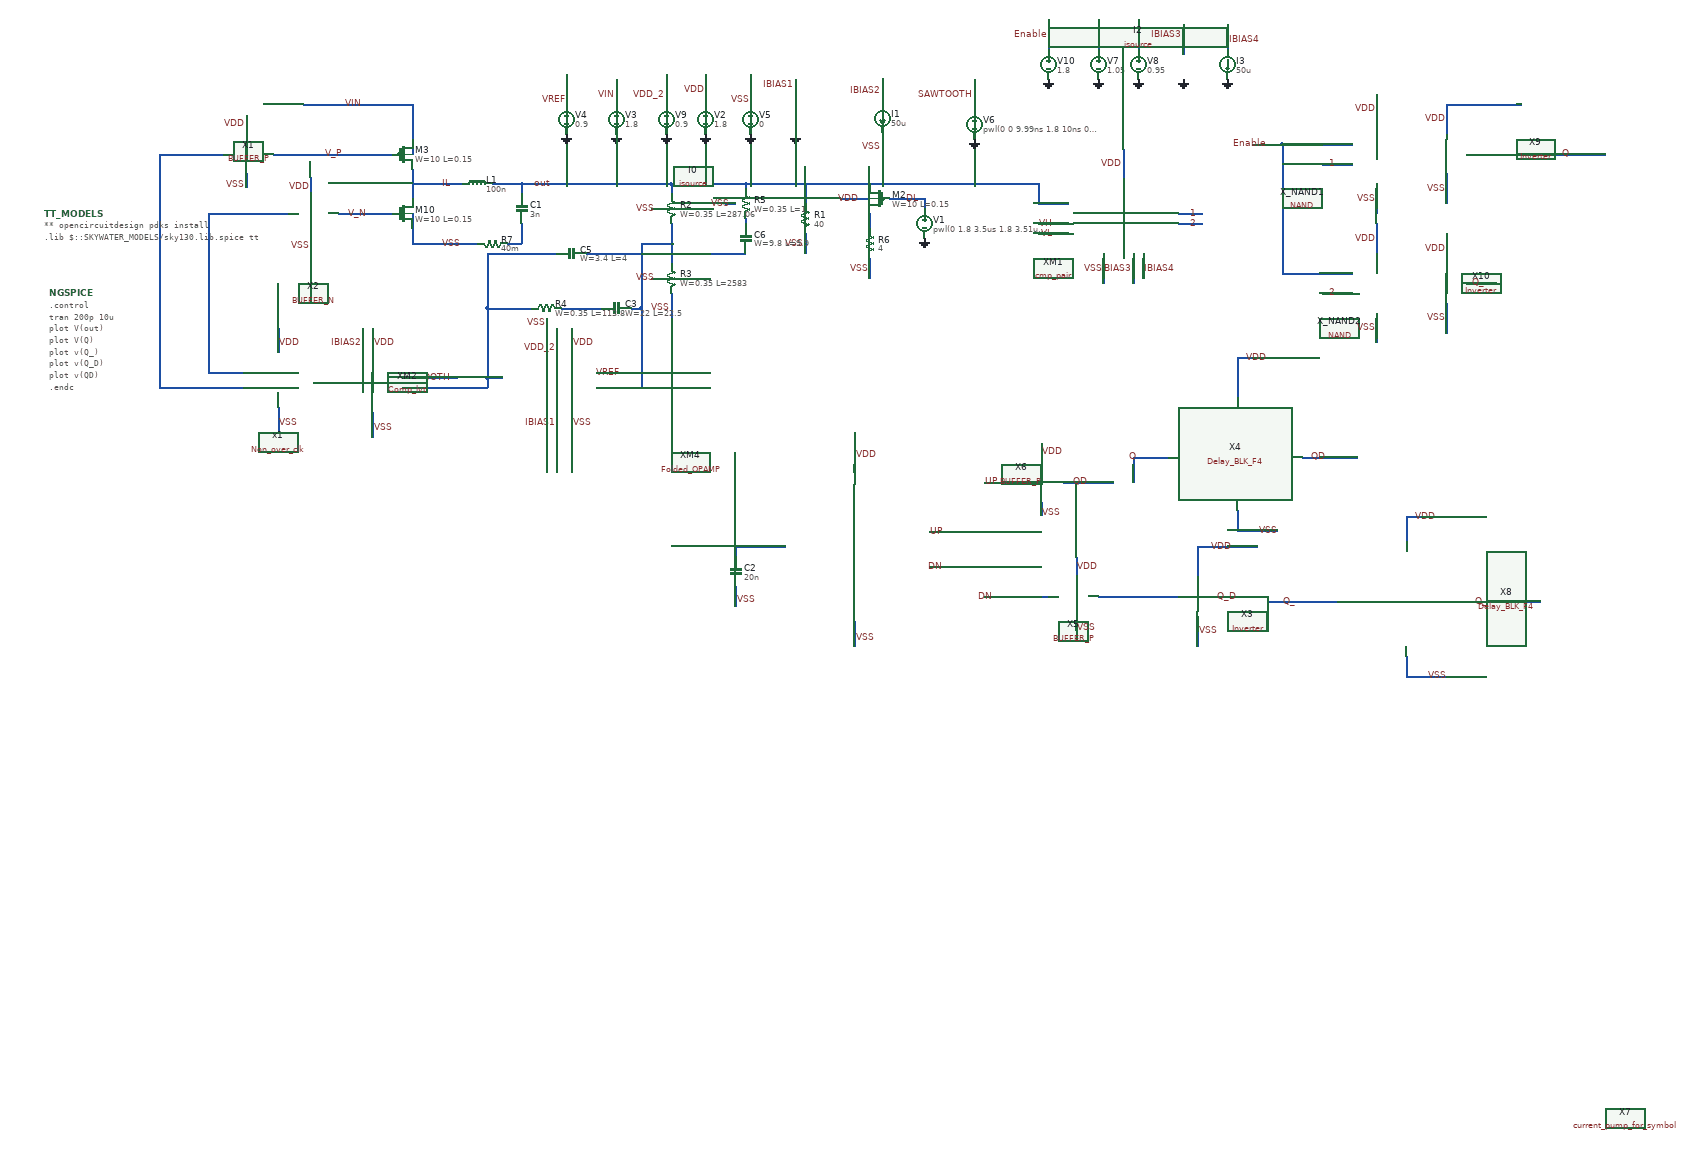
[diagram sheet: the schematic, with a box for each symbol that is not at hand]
v {xschem version=3.0.0 file_version=1.2 }
G {}
K {}
V {}
S {}
E {}
N 2100 -2270 2100 -2210 {
lab=IL}
N 2100 -2330 2100 -2300 {
lab=VIN}
N 2010 -2300 2060 -2300 {
lab=V_P}
N 2100 -2400 2100 -2330 {
lab=VIN}
N 1880 -2400 2100 -2400 {
lab=VIN}
N 2100 -2150 2100 -2120 {
lab=VSS}
N 2100 -2240 2160 -2240 {
lab=IL}
N 2160 -2240 2200 -2240 {
lab=IL}
N 2320 -2240 2320 -2220 {
lab=out}
N 2260 -2240 2320 -2240 {
lab=out}
N 2320 -2160 2320 -2120 {
lab=#net1}
N 2320 -2240 2430 -2240 {
lab=out}
N 2420 -1950 2420 -1900 {
lab=VDD}
N 2390 -1950 2390 -1900 {
lab=VDD_2}
N 2420 -1790 2420 -1740 {
lab=VSS}
N 2390 -1790 2390 -1740 {
lab=IBIAS1}
N 2470 -1830 2520 -1830 {
lab=#net2}
N 2470 -1860 2520 -1860 {
lab=VREF}
N 2510 -2450 2510 -2400 {
lab=VIN}
N 2610 -2460 2610 -2400 {
lab=VDD_2}
N 2690 -2410 2690 -2400 {
lab=VDD}
N 2690 -2460 2690 -2410 {
lab=VDD}
N 2780 -2430 2780 -2410 {
lab=VSS}
N 2780 -2410 2780 -2400 {
lab=VSS}
N 2780 -2460 2780 -2430 {
lab=VSS}
N 2870 -2450 2870 -2390 {
lab=IBIAS1}
N 2020 -1950 2020 -1900 {
lab=VDD}
N 2020 -1780 2020 -1730 {
lab=VSS}
N 2410 -2430 2410 -2410 {
lab=VREF}
N 2410 -2410 2410 -2400 {
lab=VREF}
N 2410 -2460 2410 -2430 {
lab=VREF}
N 2520 -1830 2550 -1830 {
lab=#net2}
N 3045 -2342.5 3045 -2292.5 {
lab=VSS}
N 2000 -1950 2000 -1900 {
lab=IBIAS2}
N 3230 -2450 3230 -2390 {
lab=SAWTOOTH}
N 1820 -2300 2010 -2300 {
lab=V_P}
N 2430 -2240 2610 -2240 {
lab=out}
N 2620 -2240 2620 -2220 {
lab=out}
N 2620 -2160 2620 -2110 {
lab=#net2}
N 2620 -2020 2620 -1970 {
lab=VSS}
N 2400 -1990 2480 -1990 {
lab=#net3}
N 2250 -1990 2340 -1990 {
lab=#net4}
N 2250 -1990 2250 -1850 {
lab=#net4}
N 2560 -1990 2560 -1860 {
lab=#net2}
N 2540 -1990 2560 -1990 {
lab=#net2}
N 2250 -2100 2390 -2100 {
lab=#net4}
N 2450 -2100 2560 -2100 {
lab=#net2}
N 2560 -2060 2560 -1990 {
lab=#net2}
N 2250 -1850 2280 -1850 {
lab=#net4}
N 2560 -1860 2560 -1830 {
lab=#net2}
N 2550 -1830 2560 -1830 {
lab=#net2}
N 2620 -2240 2770 -2240 {
lab=out}
N 2770 -2240 2770 -2230 {
lab=out}
N 2770 -2170 2770 -2160 {
lab=#net5}
N 2610 -2240 2620 -2240 {
lab=out}
N 2560 -2120 2560 -2060 {
lab=#net2}
N 2560 -2120 2620 -2120 {
lab=#net2}
N 2620 -2110 2620 -2080 {
lab=#net2}
N 2890 -2240 2890 -2200 {
lab=out}
N 2770 -2240 2890 -2240 {
lab=out}
N 2890 -2140 2890 -2100 {
lab=VSS}
N 2080 -1830 2250 -1830 {
lab=#net4}
N 2250 -1850 2250 -1830 {
lab=#net4}
N 2010 -2180 2060 -2180 {
lab=V_N}
N 2100 -2180 2100 -2150 {
lab=VSS}
N 2890 -2240 3020 -2240 {
lab=out}
N 3020 -2090 3020 -2050 {
lab=VSS}
N 3020 -2180 3020 -2150 {
lab=#net6}
N 3060 -2210 3130 -2210 {
lab=DL}
N 3130 -2210 3130 -2190 {
lab=DL}
N 1830 -1950 1830 -1900 {
lab=VDD}
N 1830 -1790 1830 -1740 {
lab=VSS}
N 1590 -2300 1720 -2300 {
lab=#net7}
N 1590 -2300 1590 -1860 {
lab=#net7}
N 1765 -2260 1765 -2232.5 {
lab=VSS}
N 1765 -2377.5 1765 -2342.5 {
lab=VDD}
N 1950 -2180 2010 -2180 {
lab=V_N}
N 1690 -2180 1850 -2180 {
lab=#net8}
N 1690 -2180 1690 -2090 {
lab=#net8}
N 1895 -2140 1895 -2102.5 {
lab=VSS}
N 1895 -2252.5 1895 -2222.5 {
lab=VDD}
N 1690 -1860 1750 -1860 {
lab=#net8}
N 1690 -2090 1690 -1860 {
lab=#net8}
N 1590 -1830 1750 -1830 {
lab=#net7}
N 1590 -1860 1590 -1830 {
lab=#net7}
N 2250 -2100 2250 -1990 {
lab=#net4}
N 2620 -2100 2670 -2100 {
lab=#net2}
N 2670 -2100 2770 -2100 {
lab=#net2}
N 2420 -1790 2420 -1740 {
lab=VSS}
N 2960 -2210 3020 -2210 {
lab=VDD}
N 3045 -2452.5 3045 -2402.5 {
lab=IBIAS2}
N 1900 -1840 1950 -1840 {
lab=#net9}
N 2080 -1850 2190 -1850 {
lab=SAWTOOTH}
N 2370 -1970 2370 -1950 {
lab=VSS}
N 2730 -2200 2750 -2200 {
lab=VSS}
N 2580 -2190 2600 -2190 {
lab=VSS}
N 2580 -2050 2600 -2050 {
lab=VSS}
N 2100 -2120 2230 -2120 {
lab=VSS}
N 2290 -2120 2320 -2120 {
lab=#net1}
N 3640 -2180 3690 -2180 {
lab=1}
N 3640 -2160 3690 -2160 {
lab=2}
N 3570 -2100 3570 -2050 {
lab=IBIAS4}
N 3550 -2100 3550 -2040 {
lab=IBIAS3}
N 3490 -2100 3490 -2040 {
lab=VSS}
N 3530 -2310 3530 -2250 {
lab=VDD}
N 3360 -2200 3420 -2200 {
lab=out}
N 3360 -2160 3420 -2160 {
lab=VH}
N 3360 -2140 3420 -2140 {
lab=VL}
N 3020 -2240 3360 -2240 {
lab=out}
N 3360 -2240 3360 -2200 {
lab=out}
N 3480 -2570 3480 -2510 {
lab=VH}
N 3560 -2570 3560 -2510 {
lab=VL}
N 3650 -2560 3650 -2500 {
lab=IBIAS3}
N 3740 -2560 3740 -2510 {
lab=IBIAS4}
N 4040 -2420 4040 -2360 {
lab=VDD}
N 4040 -2240 4040 -2180 {
lab=VSS}
N 4040 -2160 4040 -2100 {
lab=VDD}
N 4040 -1980 4040 -1920 {
lab=VSS}
N 3850 -2060 3990 -2060 {
lab=Enable}
N 3850 -2320 3850 -2060 {
lab=Enable}
N 3850 -2320 3990 -2320 {
lab=Enable}
N 3790 -2320 3850 -2320 {
lab=Enable}
N 3930 -2280 3990 -2280 {
lab=1}
N 3930 -2020 3990 -2020 {
lab=2}
N 4220 -2300 4280 -2300 {
lab=Q}
N 4220 -2040 4280 -2040 {
lab=Q_}
N 4180 -2400 4180 -2340 {
lab=VDD}
N 4180 -2260 4180 -2200 {
lab=VSS}
N 4180 -2140 4180 -2080 {
lab=VDD}
N 4180 -2000 4180 -1940 {
lab=VSS}
N 4280 -2300 4290 -2300 {
lab=Q}
N 4180 -2400 4330 -2400 {
lab=VDD}
N 4290 -2300 4500 -2300 {
lab=Q}
N 3380 -2570 3380 -2510 {
lab=Enable}
N 3480 -1410 3580 -1410 {
lab=#net10}
N 3410 -1640 3510 -1640 {
lab=QD}
N 3435 -1370 3435 -1342.5 {
lab=VSS}
N 3435 -1487.5 3435 -1452.5 {
lab=VDD}
N 3365 -1600 3365 -1572.5 {
lab=VSS}
N 3365 -1717.5 3365 -1682.5 {
lab=VDD}
N 3250 -1410 3310 -1410 {
lab=DN}
N 3140 -1540 3180 -1540 {
lab=UP}
N 3250 -1640 3310 -1640 {
lab=UP}
N 3140 -1470 3180 -1470 {
lab=DN}
N 2990 -1720 2990 -1660 {
lab=VDD}
N 2990 -1360 2990 -1310 {
lab=VSS}
N 2990 -1740 2990 -1720 {
lab=VDD}
N 3310 -1410 3380 -1410 {
lab=DN}
N 3580 -1410 3640 -1410 {
lab=#net10}
N 3680 -1510 3680 -1450 {
lab=VDD}
N 3680 -1370 3680 -1310 {
lab=VSS}
N 3680 -1510 3800 -1510 {
lab=VDD}
N 3550 -1690 3620 -1690 {
lab=Q}
N 3550 -1690 3550 -1640 {
lab=Q}
N 3820 -1400 3960 -1400 {
lab=Q_}
N 3820 -1410 3820 -1400 {
lab=Q_}
N 3890 -1690 4000 -1690 {
lab=QD}
N 4230 -1400 4370 -1400 {
lab=Q_D}
N 3720 -1410 3760 -1410 {
lab=Q_D}
N 3760 -1890 3760 -1810 {
lab=VDD}
N 3760 -1582.5 3760 -1542.5 {
lab=VSS}
N 3760 -1542.5 3840 -1542.5 {
lab=VSS}
N 4100 -1570 4100 -1520 {
lab=VDD}
N 4100 -1570 4130 -1570 {
lab=VDD}
N 3760 -1890 3790 -1890 {
lab=VDD}
N 4100 -1290 4100 -1250 {
lab=VSS}
N 4100 -1250 4180 -1250 {
lab=VSS}
N 2750 -1510 2750 -1490 {
lab=#net9}
N 2750 -1430 2750 -1390 {
lab=VSS}
N 2750 -1510 2850 -1510 {}
N 1750 -1860 1760 -1860 {}
N 1750 -1830 1760 -1830 {}
C {sky130_fd_pr/pfet_01v8.sym} 2080 -2300 0 0 {name=M3
L=0.15
W=10
nf=1
mult=450
ad="'int((nf+1)/2) * W/nf * 0.29'" 
pd="'2*int((nf+1)/2) * (W/nf + 0.29)'"
as="'int((nf+2)/2) * W/nf * 0.29'" 
ps="'2*int((nf+2)/2) * (W/nf + 0.29)'"
nrd="'0.29 / W'" nrs="'0.29 / W'"
sa=0 sb=0 sd=0
model=pfet_01v8
spiceprefix=X
}
C {devices/ind.sym} 2230 -2240 3 0 {name=L1
m=1
value=100n
footprint=1206
device=inductor}
C {devices/capa.sym} 2320 -2190 0 0 {name=C1
m=1
value=3n
footprint=1206
device="ceramic capacitor"}
C {devices/code.sym} 1360 -2180 0 0 {name=TT_MODELS
only_toplevel=true
format="tcleval( @value )"
value="
** opencircuitdesign pdks install
.lib $::SKYWATER_MODELS/sky130.lib.spice tt

"
spice_ignore=false}
C {devices/code_shown.sym} 1370 -2020 0 0 {name=NGSPICE
only_toplevel=true
value="

.control

tran 200p 10u
plot  V(out)
plot V(Q)
plot v(Q_) 
plot v(Q_D)
plot v(QD)
.endc
" }
C {devices/lab_wire.sym} 2380 -2240 0 0 {name=l4 sig_type=std_logic lab=out}
C {devices/lab_wire.sym} 2180 -2240 0 0 {name=l6 sig_type=std_logic lab=IL}
C {devices/lab_wire.sym} 2000 -2400 0 0 {name=l5 sig_type=std_logic lab=VIN}
C {devices/vsource.sym} 2510 -2370 0 0 {name=V3 value=1.8}
C {devices/gnd.sym} 2510 -2340 0 0 {name=l7 lab=GND}
C {devices/lab_wire.sym} 2510 -2420 0 0 {name=l2 sig_type=std_logic lab=VIN}
C {devices/gnd.sym} 2870 -2340 0 0 {name=l19 lab=GND}
C {devices/lab_wire.sym} 2870 -2440 0 0 {name=l22 sig_type=std_logic lab=IBIAS1}
C {devices/isource.sym} 2870 -2370 0 0 {name=I0 value=50u}
C {devices/vsource.sym} 2610 -2370 0 0 {name=V9 value=0.9}
C {devices/gnd.sym} 2610 -2340 0 0 {name=l42 lab=GND}
C {devices/lab_wire.sym} 2610 -2420 0 0 {name=l8 sig_type=std_logic lab=VDD_2}
C {devices/vsource.sym} 2690 -2370 0 0 {name=V2 value=1.8}
C {devices/gnd.sym} 2690 -2340 0 0 {name=l18 lab=GND}
C {devices/vsource.sym} 2780 -2370 0 0 {name=V5 value=0}
C {devices/gnd.sym} 2780 -2340 0 0 {name=l26 lab=GND}
C {devices/lab_wire.sym} 2780 -2410 0 0 {name=l10 sig_type=std_logic lab=VSS}
C {devices/lab_wire.sym} 2420 -1920 0 1 {name=l13 sig_type=std_logic lab=VDD}
C {devices/lab_wire.sym} 2390 -1910 0 0 {name=l14 sig_type=std_logic lab=VDD_2}
C {devices/lab_wire.sym} 2200 -2120 0 0 {name=l1 sig_type=std_logic lab=VSS}
C {devices/lab_wire.sym} 2420 -1760 0 1 {name=l15 sig_type=std_logic lab=VSS}
C {devices/lab_wire.sym} 2390 -1760 0 0 {name=l16 sig_type=std_logic lab=IBIAS1}
C {devices/lab_wire.sym} 2020 -1920 0 1 {name=l11 sig_type=std_logic lab=VDD}
C {devices/lab_wire.sym} 2020 -1750 0 1 {name=l12 sig_type=std_logic lab=VSS}
C {devices/vsource.sym} 2410 -2370 0 0 {name=V4 value=0.9}
C {devices/gnd.sym} 2410 -2340 0 0 {name=l17 lab=GND}
C {devices/lab_wire.sym} 2410 -2410 0 0 {name=l20 sig_type=std_logic lab=VREF}
C {devices/isource.sym} 3045 -2372.5 0 1 {name=I1 value=50u}
C {devices/lab_wire.sym} 2000 -1920 0 0 {name=l27 sig_type=std_logic lab=IBIAS2}
C {devices/vsource.sym} 3230 -2360 0 0 {name=V6 value="pwl(0 0 9.99ns 1.8 10ns 0) r=0"}
C {devices/gnd.sym} 3230 -2330 0 0 {name=l28 lab=GND}
C {devices/gnd.sym} 3230 -2330 0 0 {name=l29 lab=GND}
C {devices/lab_wire.sym} 3230 -2420 0 0 {name=l30 sig_type=std_logic lab=SAWTOOTH}
C {devices/lab_wire.sym} 2620 -1990 0 0 {name=l31 sig_type=std_logic lab=VSS}
C {devices/lab_wire.sym} 2520 -1860 0 0 {name=l33 sig_type=std_logic lab=VREF}
C {devices/lab_wire.sym} 2180 -1850 0 0 {name=l32 sig_type=std_logic lab=SAWTOOTH}
C {devices/lab_wire.sym} 2890 -2120 0 0 {name=l21 sig_type=std_logic lab=VSS}
C {sky130_fd_pr/pfet_01v8.sym} 3040 -2210 0 1 {name=M2
L=0.15
W=10
nf=1
mult=450
ad="'int((nf+1)/2) * W/nf * 0.29'" 
pd="'2*int((nf+1)/2) * (W/nf + 0.29)'"
as="'int((nf+2)/2) * W/nf * 0.29'" 
ps="'2*int((nf+2)/2) * (W/nf + 0.29)'"
nrd="'0.29 / W'" nrs="'0.29 / W'"
sa=0 sb=0 sd=0
model=pfet_01v8
spiceprefix=X
}
C {devices/lab_wire.sym} 3020 -2070 0 0 {name=l23 sig_type=std_logic lab=VSS}
C {devices/vsource.sym} 3130 -2160 0 0 {name=V1 value="pwl(0 1.8 3.5us 1.8 3.51us 0 7us 0) r=0"}
C {devices/gnd.sym} 3130 -2130 0 0 {name=l34 lab=GND}
C {devices/gnd.sym} 3130 -2130 0 0 {name=l36 lab=GND}
C {devices/lab_wire.sym} 1830 -1920 0 1 {name=l35 sig_type=std_logic lab=VDD}
C {devices/lab_wire.sym} 1830 -1760 0 1 {name=l37 sig_type=std_logic lab=VSS}
C {DC_DC_Converter/BUFFER/BUFFER_PMOS/BUFFER_P.sym} 1700 -2250 0 0 {name=X1}
C {devices/lab_wire.sym} 1765 -2360 0 0 {name=l38 sig_type=std_logic lab=VDD}
C {devices/lab_wire.sym} 1765 -2237.5 0 0 {name=l40 sig_type=std_logic lab=VSS}
C {devices/lab_wire.sym} 1895 -2115 0 0 {name=l39 sig_type=std_logic lab=VSS}
C {devices/lab_wire.sym} 1895 -2235 0 0 {name=l41 sig_type=std_logic lab=VDD}
C {devices/lab_wire.sym} 1960 -2300 0 0 {name=l3 sig_type=std_logic lab=V_P}
C {devices/lab_wire.sym} 2010 -2180 0 0 {name=l43 sig_type=std_logic lab=V_N}
C {DC_DC_Converter/Folded_OPAMP/Folded_OPAMP.sym} 2480 -1790 0 1 {name=XM4}
C {devices/lab_wire.sym} 3120 -2210 0 0 {name=l96 sig_type=std_logic lab=DL}
C {sky130_fd_pr/cap_mim_m3_1.sym} 2420 -2100 3 0 {name=C5 model=cap_mim_m3_1 W=3.4 L=4 MF=1 spiceprefix=X}
C {sky130_fd_pr/cap_mim_m3_1.sym} 2510 -1990 3 0 {name=C3 model=cap_mim_m3_1 W=22 L=22.5 MF=1 spiceprefix=X}
C {sky130_fd_pr/cap_mim_m3_1.sym} 2770 -2130 0 0 {name=C6 model=cap_mim_m3_1 W=9.8 L=9.9 MF=1 spiceprefix=X}
C {devices/lab_wire.sym} 2690 -2430 0 0 {name=l97 sig_type=std_logic lab=VDD}
C {devices/lab_wire.sym} 3000 -2210 0 0 {name=l98 sig_type=std_logic lab=VDD}
C {sky130_fd_pr/nfet_01v8.sym} 2080 -2180 0 0 {name=M10
L=0.15
W=10
nf=1 
mult=150
ad="'int((nf+1)/2) * W/nf * 0.29'" 
pd="'2*int((nf+1)/2) * (W/nf + 0.29)'"
as="'int((nf+2)/2) * W/nf * 0.29'" 
ps="'2*int((nf+2)/2) * (W/nf + 0.29)'"
nrd="'0.29 / W'" nrs="'0.29 / W'"
sa=0 sb=0 sd=0
model=nfet_01v8
spiceprefix=X
}
C {DC_DC_Converter/Comparator/Comp_lvt.sym} 2100 -1770 0 1 {name=XM2}
C {devices/lab_wire.sym} 3045 -2427.5 0 0 {name=l24 sig_type=std_logic lab=IBIAS2}
C {devices/lab_wire.sym} 3045 -2315 0 0 {name=l25 sig_type=std_logic lab=VSS}
C {sky130_fd_pr/res_high_po_0p35.sym} 2370 -1990 3 0 {name=R4
W=0.35
L=113.8
model=res_high_po_0p35
spiceprefix=X
mult=1}
C {devices/lab_wire.sym} 2370 -1960 3 0 {name=l9 sig_type=std_logic lab=VSS}
C {sky130_fd_pr/res_high_po_0p35.sym} 2770 -2200 0 0 {name=R5
W=0.35
L=1
model=res_high_po_0p35
spiceprefix=X
mult=1}
C {devices/lab_wire.sym} 2740 -2200 0 0 {name=l44 sig_type=std_logic lab=VSS}
C {sky130_fd_pr/res_high_po_0p35.sym} 2620 -2190 0 0 {name=R2
W=0.35
L=287.06
model=res_high_po_0p35
spiceprefix=X
mult=1}
C {devices/lab_wire.sym} 2590 -2190 0 0 {name=l45 sig_type=std_logic lab=VSS}
C {sky130_fd_pr/res_high_po_0p35.sym} 2620 -2050 0 0 {name=R3
W=0.35
L=2583
model=res_high_po_0p35
spiceprefix=X
mult=1}
C {devices/lab_wire.sym} 2590 -2050 0 0 {name=l46 sig_type=std_logic lab=VSS}
C {devices/res.sym} 2260 -2120 1 0 {name=R7
value=40m
footprint=1206
device=resistor
m=1}
C {devices/res.sym} 2890 -2170 0 0 {name=R1
value=40
footprint=1206
device=resistor
m=1}
C {devices/res.sym} 3020 -2120 0 0 {name=R6
value=4
footprint=1206
device=resistor
m=1}
C {devices/lab_wire.sym} 3570 -2070 0 1 {name=l48 sig_type=std_logic lab=IBIAS4}
C {devices/lab_wire.sym} 3550 -2070 0 0 {name=l49 sig_type=std_logic lab=IBIAS3}
C {devices/lab_pin.sym} 3490 -2070 0 0 {name=l50 sig_type=std_logic lab=VSS}
C {devices/lab_pin.sym} 3530 -2280 0 0 {name=l51 sig_type=std_logic lab=VDD}
C {devices/lab_pin.sym} 3390 -2160 1 0 {name=l53 sig_type=std_logic lab=VH}
C {devices/lab_pin.sym} 3390 -2140 3 0 {name=l54 sig_type=std_logic lab=VL}
C {DC_DC_Converter/Comparator_Pair/cmp_pair.sym} 3400 -2100 0 0 {name=XM1}
C {devices/lab_wire.sym} 3680 -2180 0 0 {name=l47 sig_type=std_logic lab=1}
C {devices/lab_wire.sym} 3680 -2160 0 0 {name=l87 sig_type=std_logic lab=2}
C {devices/vsource.sym} 3480 -2480 0 0 {name=V7 value=1.05}
C {devices/gnd.sym} 3480 -2450 0 0 {name=l52 lab=GND}
C {devices/lab_pin.sym} 3480 -2540 0 0 {name=l55 sig_type=std_logic lab=VH}
C {devices/vsource.sym} 3560 -2480 0 0 {name=V8 value=0.95}
C {devices/gnd.sym} 3560 -2450 0 0 {name=l56 lab=GND}
C {devices/lab_pin.sym} 3560 -2540 0 0 {name=l57 sig_type=std_logic lab=VL}
C {devices/gnd.sym} 3650 -2450 0 0 {name=l58 lab=GND}
C {devices/isource.sym} 3650 -2480 0 0 {name=I2 value=50u}
C {devices/isource.sym} 3740 -2480 0 0 {name=I3 value=50u}
C {devices/gnd.sym} 3740 -2450 0 0 {name=l60 lab=GND}
C {devices/lab_wire.sym} 3650 -2540 0 0 {name=l59 sig_type=std_logic lab=IBIAS3}
C {devices/lab_wire.sym} 3740 -2530 0 1 {name=l61 sig_type=std_logic lab=IBIAS4}
C {devices/noconn.sym} 3690 -2160 0 1 {name=l62}
C {devices/noconn.sym} 3690 -2180 0 1 {name=l63}
C {DC_DC_Converter/NAND_GATE/NAND.sym} 3970 -2230 0 0 {name=X_NAND1}
C {devices/lab_pin.sym} 4040 -2390 0 0 {name=l81 sig_type=std_logic lab=VDD}
C {devices/lab_pin.sym} 4040 -2210 0 0 {name=l82 sig_type=std_logic lab=VSS}
C {DC_DC_Converter/NAND_GATE/NAND.sym} 3970 -1970 0 0 {name=X_NAND2}
C {devices/lab_pin.sym} 4040 -2130 0 0 {name=l83 sig_type=std_logic lab=VDD}
C {devices/lab_pin.sym} 4040 -1950 0 0 {name=l84 sig_type=std_logic lab=VSS}
C {DC_DC_Converter/Inverter/Inverter.sym} 4110 -2280 0 0 {name=X9}
C {DC_DC_Converter/Inverter/Inverter.sym} 4110 -2020 0 0 {name=X10}
C {devices/lab_wire.sym} 4260 -2040 0 0 {name=l86 sig_type=std_logic lab=Q_}
C {devices/lab_wire.sym} 3960 -2280 0 0 {name=l64 sig_type=std_logic lab=1}
C {devices/lab_wire.sym} 3960 -2020 0 0 {name=l88 sig_type=std_logic lab=2}
C {devices/lab_wire.sym} 3820 -2320 0 0 {name=l91 sig_type=std_logic lab=Enable}
C {devices/lab_pin.sym} 4180 -2370 0 0 {name=l92 sig_type=std_logic lab=VDD}
C {devices/lab_pin.sym} 4180 -2230 0 0 {name=l93 sig_type=std_logic lab=VSS}
C {devices/lab_pin.sym} 4180 -2110 0 0 {name=l94 sig_type=std_logic lab=VDD}
C {devices/lab_pin.sym} 4180 -1970 0 0 {name=l95 sig_type=std_logic lab=VSS}
C {devices/lab_wire.sym} 4430 -2300 0 0 {name=l79 sig_type=std_logic lab=Q}
C {devices/gnd.sym} 3380 -2450 0 0 {name=l89 lab=GND}
C {devices/lab_pin.sym} 3380 -2540 0 0 {name=l90 sig_type=std_logic lab=Enable}
C {devices/vsource.sym} 3380 -2480 0 0 {name=V10 value=1.8}
C {DC_DC_Converter/BUFFER/BUFFER_PMOS/BUFFER_P.sym} 3500 -1360 0 1 {name=X5}
C {devices/lab_wire.sym} 3435 -1470 0 1 {name=l68 sig_type=std_logic lab=VDD}
C {devices/lab_wire.sym} 3435 -1347.5 0 1 {name=l69 sig_type=std_logic lab=VSS}
C {DC_DC_Converter/BUFFER/BUFFER_PMOS/BUFFER_P.sym} 3430 -1590 0 1 {name=X6}
C {devices/lab_wire.sym} 3365 -1700 0 1 {name=l70 sig_type=std_logic lab=VDD}
C {devices/lab_wire.sym} 3365 -1577.5 0 1 {name=l71 sig_type=std_logic lab=VSS}
C {DC_DC_Converter/current_pump/current_pump_for_symbol.sym} 4540 -360 0 1 {name=X7}
C {devices/lab_wire.sym} 3270 -1410 0 0 {name=l75 sig_type=std_logic lab=DN}
C {devices/lab_wire.sym} 3280 -1640 0 0 {name=l76 sig_type=std_logic lab=UP}
C {devices/lab_wire.sym} 2990 -1327.5 0 1 {name=l65 sig_type=std_logic lab=VSS}
C {devices/lab_wire.sym} 2990 -1695 0 1 {name=l78 sig_type=std_logic lab=VDD}
C {DC_DC_Converter/Inverter/Inverter.sym} 3750 -1390 0 1 {name=X3}
C {devices/lab_pin.sym} 3680 -1340 0 1 {name=l66 sig_type=std_logic lab=VSS}
C {devices/lab_wire.sym} 3170 -1540 0 0 {name=l67 sig_type=std_logic lab=UP}
C {devices/lab_wire.sym} 3170 -1470 0 0 {name=l72 sig_type=std_logic lab=DN}
C {devices/lab_wire.sym} 3560 -1690 0 0 {name=l110 sig_type=std_logic lab=Q}
C {devices/lab_wire.sym} 3880 -1400 0 0 {name=l111 sig_type=std_logic lab=Q_
}
C {devices/lab_wire.sym} 3705 -1510 0 1 {name=l73 sig_type=std_logic lab=VDD}
C {devices/lab_wire.sym} 3940 -1690 0 0 {name=l74 sig_type=std_logic lab=QD}
C {devices/lab_wire.sym} 4280 -1400 0 0 {name=l77 sig_type=std_logic lab=Q_D
}
C {devices/lab_wire.sym} 3460 -1640 0 0 {name=l80 sig_type=std_logic lab=QD}
C {devices/lab_wire.sym} 3760 -1410 0 0 {name=l85 sig_type=std_logic lab=Q_D
}
C {devices/lab_pin.sym} 3800 -1542.5 0 1 {name=l100 sig_type=std_logic lab=VSS}
C {devices/lab_wire.sym} 4115 -1570 0 1 {name=l101 sig_type=std_logic lab=VDD}
C {DC_DC_Converter/DELAY_JAWAD/Delay_BLK_F4.sym} 3710 -1687.5 0 0 {name=X4}
C {DC_DC_Converter/DELAY_JAWAD/Delay_BLK_F4.sym} 4050 -1397.5 0 0 {name=X8}
C {devices/lab_wire.sym} 3775 -1890 0 1 {name=l103 sig_type=std_logic lab=VDD}
C {devices/lab_pin.sym} 4140 -1250 0 1 {name=l104 sig_type=std_logic lab=VSS}
C {devices/capa.sym} 2750 -1460 0 0 {name=C2
m=1
value=20n
footprint=1206
device="ceramic capacitor"}
C {devices/lab_wire.sym} 2750 -1402.5 0 1 {name=l99 sig_type=std_logic lab=VSS}
C {DC_DC_Converter/Non_Overlap_Clk/Non_over_clk.sym} 2030 -1580 0 1 {name=x1}
C {DC_DC_Converter/BUFFER/BUFFER_NMOS/BUFFER_N.sym} 1760 -2100 0 0 {name=X2}
